VERSION 5.8 ;
BUSBITCHARS "[]" ;
DIVIDERCHAR "/" ;
UNITS
    DATABASE MICRONS 1000 ;
END UNITS

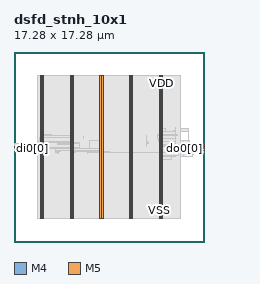
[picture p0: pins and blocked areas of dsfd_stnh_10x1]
MACRO dsfd_stnh_10x1
  FOREIGN dsfd_stnh_10x1 0 0 ;
  CLASS BLOCK ;
  SIZE 17.28 BY 17.28 ;
  PIN di0[0]
    DIRECTION INPUT ;
    USE SIGNAL ;
    PORT
      LAYER M4 ;
        RECT  0 8.496 0.084 8.52 ;
    END
  END di0[0]
  PIN di0[1]
    DIRECTION INPUT ;
    USE SIGNAL ;
    PORT
      LAYER M4 ;
        RECT  0 8.544 0.084 8.568 ;
    END
  END di0[1]
  PIN di0[2]
    DIRECTION INPUT ;
    USE SIGNAL ;
    PORT
      LAYER M4 ;
        RECT  0 8.592 0.084 8.616 ;
    END
  END di0[2]
  PIN di0[3]
    DIRECTION INPUT ;
    USE SIGNAL ;
    PORT
      LAYER M4 ;
        RECT  0 8.64 0.084 8.664 ;
    END
  END di0[3]
  PIN di0[4]
    DIRECTION INPUT ;
    USE SIGNAL ;
    PORT
      LAYER M4 ;
        RECT  0 8.688 0.084 8.712 ;
    END
  END di0[4]
  PIN di0[5]
    DIRECTION INPUT ;
    USE SIGNAL ;
    PORT
      LAYER M4 ;
        RECT  0 8.736 0.084 8.76 ;
    END
  END di0[5]
  PIN di0[6]
    DIRECTION INPUT ;
    USE SIGNAL ;
    PORT
      LAYER M4 ;
        RECT  0 8.784 0.084 8.808 ;
    END
  END di0[6]
  PIN di0[7]
    DIRECTION INPUT ;
    USE SIGNAL ;
    PORT
      LAYER M4 ;
        RECT  0 8.832 0.084 8.856 ;
    END
  END di0[7]
  PIN di0[8]
    DIRECTION INPUT ;
    USE SIGNAL ;
    PORT
      LAYER M4 ;
        RECT  0 8.88 0.084 8.904 ;
    END
  END di0[8]
  PIN di0[9]
    DIRECTION INPUT ;
    USE SIGNAL ;
    PORT
      LAYER M4 ;
        RECT  0 8.928 0.084 8.952 ;
    END
  END di0[9]
  PIN do0[0]
    DIRECTION OUTPUT ;
    USE SIGNAL ;
    PORT
      LAYER M4 ;
        RECT  17.196 8.496 17.28 8.52 ;
    END
  END do0[0]
  PIN do0[1]
    DIRECTION OUTPUT ;
    USE SIGNAL ;
    PORT
      LAYER M4 ;
        RECT  17.196 8.544 17.28 8.568 ;
    END
  END do0[1]
  PIN do0[2]
    DIRECTION OUTPUT ;
    USE SIGNAL ;
    PORT
      LAYER M4 ;
        RECT  17.196 8.592 17.28 8.616 ;
    END
  END do0[2]
  PIN do0[3]
    DIRECTION OUTPUT ;
    USE SIGNAL ;
    PORT
      LAYER M4 ;
        RECT  17.196 8.64 17.28 8.664 ;
    END
  END do0[3]
  PIN do0[4]
    DIRECTION OUTPUT ;
    USE SIGNAL ;
    PORT
      LAYER M4 ;
        RECT  17.196 8.688 17.28 8.712 ;
    END
  END do0[4]
  PIN do0[5]
    DIRECTION OUTPUT ;
    USE SIGNAL ;
    PORT
      LAYER M4 ;
        RECT  17.196 8.736 17.28 8.76 ;
    END
  END do0[5]
  PIN do0[6]
    DIRECTION OUTPUT ;
    USE SIGNAL ;
    PORT
      LAYER M4 ;
        RECT  17.196 8.784 17.28 8.808 ;
    END
  END do0[6]
  PIN do0[7]
    DIRECTION OUTPUT ;
    USE SIGNAL ;
    PORT
      LAYER M4 ;
        RECT  17.196 8.832 17.28 8.856 ;
    END
  END do0[7]
  PIN do0[8]
    DIRECTION OUTPUT ;
    USE SIGNAL ;
    PORT
      LAYER M4 ;
        RECT  17.196 8.88 17.28 8.904 ;
    END
  END do0[8]
  PIN do0[9]
    DIRECTION OUTPUT ;
    USE SIGNAL ;
    PORT
      LAYER M4 ;
        RECT  17.196 8.928 17.28 8.952 ;
    END
  END do0[9]
  PIN fi0[0]
    DIRECTION INPUT ;
    USE SIGNAL ;
    PORT
      LAYER M4 ;
        RECT  0 8.304 0.084 8.328 ;
    END
  END fi0[0]
  PIN fo0[0]
    DIRECTION OUTPUT ;
    USE SIGNAL ;
    PORT
      LAYER M4 ;
        RECT  17.196 8.304 17.28 8.328 ;
    END
  END fo0[0]
  PIN VDD
    DIRECTION INOUT ;
    USE POWER ;
    PORT
      LAYER M5 ;
        RECT  13.392 2.151 13.512 15.129 ;
        RECT  10.692 2.151 10.812 15.129 ;
        RECT  7.992 2.151 8.112 15.129 ;
        RECT  5.292 2.151 5.412 15.129 ;
        RECT  2.592 2.151 2.712 15.129 ;
    END
  END VDD
  PIN VSS
    DIRECTION INOUT ;
    USE GROUND ;
    PORT
      LAYER M5 ;
        RECT  13.2 2.137 13.32 15.143 ;
        RECT  10.5 2.137 10.62 15.143 ;
        RECT  7.8 2.137 7.92 15.143 ;
        RECT  5.1 2.137 5.22 15.143 ;
        RECT  2.4 2.137 2.52 15.143 ;
    END
  END VSS
  OBS
    LAYER RVTN ;
     RECT  2.16 2.16 15.12 2.295 ;
     RECT  2.16 2.565 15.12 2.835 ;
     RECT  2.16 3.105 15.12 3.375 ;
     RECT  2.16 3.645 15.12 3.915 ;
     RECT  2.16 4.185 15.12 4.455 ;
     RECT  2.16 4.725 15.12 4.995 ;
     RECT  2.16 5.265 15.12 5.535 ;
     RECT  2.16 5.805 15.12 6.075 ;
     RECT  2.16 6.345 15.12 6.615 ;
     RECT  2.16 6.885 15.12 7.155 ;
     RECT  2.16 7.425 15.12 7.695 ;
     RECT  2.16 7.965 15.12 8.235 ;
     RECT  2.16 8.505 15.12 8.775 ;
     RECT  2.16 9.045 15.12 9.315 ;
     RECT  2.16 9.585 15.12 9.855 ;
     RECT  2.16 10.125 15.12 10.395 ;
     RECT  2.16 10.665 15.12 10.935 ;
     RECT  2.16 11.205 15.12 11.475 ;
     RECT  2.16 11.745 15.12 12.015 ;
     RECT  2.16 12.285 15.12 12.555 ;
     RECT  2.16 12.825 15.12 13.095 ;
     RECT  2.16 13.365 15.12 13.635 ;
     RECT  2.16 13.905 15.12 14.175 ;
     RECT  2.16 14.445 15.12 14.715 ;
     RECT  2.16 14.985 15.12 15.12 ;
    LAYER RVTP ;
     RECT  2.16 2.295 15.12 2.565 ;
     RECT  2.16 2.835 15.12 3.105 ;
     RECT  2.16 3.375 15.12 3.645 ;
     RECT  2.16 3.915 15.12 4.185 ;
     RECT  2.16 4.455 15.12 4.725 ;
     RECT  2.16 4.995 15.12 5.265 ;
     RECT  2.16 5.535 15.12 5.805 ;
     RECT  2.16 6.075 15.12 6.345 ;
     RECT  2.16 6.615 15.12 6.885 ;
     RECT  2.16 7.155 15.12 7.425 ;
     RECT  2.16 7.695 15.12 7.965 ;
     RECT  2.16 8.235 15.12 8.505 ;
     RECT  2.16 8.775 15.12 9.045 ;
     RECT  2.16 9.315 15.12 9.585 ;
     RECT  2.16 9.855 15.12 10.125 ;
     RECT  2.16 10.395 15.12 10.665 ;
     RECT  2.16 10.935 15.12 11.205 ;
     RECT  2.16 11.475 15.12 11.745 ;
     RECT  2.16 12.015 15.12 12.285 ;
     RECT  2.16 12.555 15.12 12.825 ;
     RECT  2.16 13.095 15.12 13.365 ;
     RECT  2.16 13.635 15.12 13.905 ;
     RECT  2.16 14.175 15.12 14.445 ;
     RECT  2.16 14.715 15.12 14.985 ;
    LAYER M1 ;
     RECT  2.16 2.151 15.12 15.129 ;
    LAYER M2 ;
     RECT  0.139 8.28 0.175 8.298 ;
     RECT  0.175 8.28 2.16 8.46 ;
     RECT  2.16 2.151 15.12 15.129 ;
     RECT  15.12 7.776 15.431 9.234 ;
     RECT  15.12 10.026 15.863 10.314 ;
     RECT  15.863 10.026 15.899 10.044 ;
     RECT  15.431 8.946 15.935 9.234 ;
     RECT  15.935 9.216 15.971 9.234 ;
     RECT  15.431 7.776 16.007 8.154 ;
     RECT  16.007 7.776 16.259 7.956 ;
     RECT  16.259 7.938 16.331 7.956 ;
    LAYER M3 ;
     RECT  2.415 2.143 2.505 2.413 ;
     RECT  5.115 2.143 5.205 2.413 ;
     RECT  7.815 2.143 7.905 2.413 ;
     RECT  10.515 2.143 10.605 2.413 ;
     RECT  13.215 2.143 13.305 2.413 ;
     RECT  13.215 2.413 13.497 7.465 ;
     RECT  13.215 7.465 14.13 7.501 ;
     RECT  13.215 7.501 14.31 7.771 ;
     RECT  13.215 7.771 14.67 7.861 ;
     RECT  13.215 7.861 14.85 7.897 ;
     RECT  16.236 7.771 16.254 7.933 ;
     RECT  3.996 8.041 4.014 8.131 ;
     RECT  6.66 8.041 6.678 8.131 ;
     RECT  7.815 2.413 8.097 8.131 ;
     RECT  16.236 7.933 16.326 8.131 ;
     RECT  3.996 8.131 4.05 8.167 ;
     RECT  5.115 2.413 5.397 8.167 ;
     RECT  6.66 8.131 8.658 8.189 ;
     RECT  6.66 8.189 8.478 8.195 ;
     RECT  3.78 8.167 4.05 8.203 ;
     RECT  6.66 8.195 8.097 8.203 ;
     RECT  5.115 8.167 5.598 8.239 ;
     RECT  6.336 8.203 8.097 8.239 ;
     RECT  3.78 8.203 4.194 8.311 ;
     RECT  5.115 8.239 8.097 8.311 ;
     RECT  17.172 8.155 17.19 8.333 ;
     RECT  0.144 8.275 0.162 8.437 ;
     RECT  2.415 2.413 2.697 8.473 ;
     RECT  3.78 8.311 8.097 8.473 ;
     RECT  2.415 8.473 8.097 8.501 ;
     RECT  0.144 8.437 0.198 8.573 ;
     RECT  2.415 8.501 5.922 8.587 ;
     RECT  15.984 8.131 16.326 8.587 ;
     RECT  2.304 8.587 5.922 8.635 ;
     RECT  15.948 8.587 16.326 8.669 ;
     RECT  0.18 8.573 0.198 8.717 ;
     RECT  15.948 8.669 15.966 8.731 ;
     RECT  13.215 7.897 14.994 8.779 ;
     RECT  15.912 8.731 15.966 8.779 ;
     RECT  13.215 8.779 15.966 8.879 ;
     RECT  13.215 8.879 14.85 8.909 ;
     RECT  12.024 8.707 12.042 8.941 ;
     RECT  2.232 8.635 5.922 9.011 ;
     RECT  12.024 8.941 12.222 9.041 ;
     RECT  2.232 9.011 5.526 9.077 ;
     RECT  12.024 9.041 12.114 9.113 ;
     RECT  13.215 8.909 14.67 9.121 ;
     RECT  2.232 9.077 5.454 9.149 ;
     RECT  6.84 8.501 8.097 9.239 ;
     RECT  15.84 8.879 15.966 9.239 ;
     RECT  6.84 9.239 6.858 9.275 ;
     RECT  13.104 9.121 14.67 9.391 ;
     RECT  7.815 9.239 8.097 9.517 ;
     RECT  2.304 9.149 5.454 9.545 ;
     RECT  6.336 9.391 6.354 9.581 ;
     RECT  2.376 9.545 5.454 9.653 ;
     RECT  13.032 9.391 14.67 9.661 ;
     RECT  2.376 9.653 4.014 9.689 ;
     RECT  7.815 9.517 8.118 9.689 ;
     RECT  12.024 9.113 12.042 9.689 ;
     RECT  2.376 9.689 3.402 9.779 ;
     RECT  13.032 9.661 14.85 9.779 ;
     RECT  2.376 9.779 2.697 9.815 ;
     RECT  13.215 9.779 14.85 9.815 ;
     RECT  13.215 9.815 14.67 10.049 ;
     RECT  15.84 9.239 15.894 10.049 ;
     RECT  14.544 10.049 14.67 10.121 ;
     RECT  13.215 10.049 13.734 10.319 ;
     RECT  15.84 10.049 15.858 10.319 ;
     RECT  14.652 10.121 14.67 10.391 ;
     RECT  2.415 9.815 2.697 14.867 ;
     RECT  5.115 9.653 5.397 14.867 ;
     RECT  7.815 9.689 8.097 14.867 ;
     RECT  10.515 2.413 10.797 14.867 ;
     RECT  13.215 10.319 13.497 14.867 ;
     RECT  2.415 14.867 2.505 15.137 ;
     RECT  5.115 14.867 5.205 15.137 ;
     RECT  7.815 14.867 7.905 15.137 ;
     RECT  10.515 14.867 10.605 15.137 ;
     RECT  13.215 14.867 13.305 15.137 ;
    LAYER M4 ;
     RECT  0.06 8.304 2.293 8.952 ;
     RECT  2.293 8.304 2.408 9.048 ;
     RECT  2.408 2.148 2.512 15.132 ;
     RECT  2.512 2.418 2.704 14.862 ;
     RECT  2.704 9.024 3.985 9.048 ;
     RECT  3.985 8.88 4.025 9.048 ;
     RECT  4.025 8.88 5.108 9 ;
     RECT  5.108 2.148 5.212 15.132 ;
     RECT  5.212 2.418 5.404 14.862 ;
     RECT  5.404 8.976 5.933 9 ;
     RECT  7.333 8.16 7.808 8.184 ;
     RECT  7.808 2.148 7.912 15.132 ;
     RECT  7.912 2.418 8.104 14.862 ;
     RECT  8.104 8.16 10.508 8.184 ;
     RECT  10.508 2.148 10.612 15.132 ;
     RECT  10.612 2.418 10.804 14.862 ;
     RECT  10.804 8.16 13.208 8.184 ;
     RECT  13.208 2.148 13.312 15.132 ;
     RECT  13.312 2.418 13.504 14.862 ;
     RECT  13.504 8.16 14.821 8.712 ;
     RECT  14.821 8.16 15.829 8.904 ;
     RECT  15.829 8.16 17.201 8.952 ;
     RECT  17.201 8.304 17.244 8.952 ;
    LAYER M5 ;
     RECT  2.4 2.137 2.52 2.151 ;
     RECT  5.1 2.137 5.22 2.151 ;
     RECT  7.8 2.137 7.92 2.151 ;
     RECT  10.5 2.137 10.62 2.151 ;
     RECT  13.2 2.137 13.32 2.151 ;
     RECT  2.4 2.151 2.712 8.293 ;
     RECT  2.304 8.293 2.712 9.059 ;
     RECT  2.4 9.059 2.712 15.129 ;
     RECT  5.1 2.151 5.412 15.129 ;
     RECT  7.8 2.151 8.112 15.129 ;
     RECT  10.5 2.151 10.812 15.129 ;
     RECT  13.2 2.151 13.512 15.129 ;
     RECT  2.4 15.129 2.52 15.143 ;
     RECT  5.1 15.129 5.22 15.143 ;
     RECT  7.8 15.129 7.92 15.143 ;
     RECT  10.5 15.129 10.62 15.143 ;
     RECT  13.2 15.129 13.32 15.143 ;
  END
END dsfd_stnh_10x1
END LIBRARY
